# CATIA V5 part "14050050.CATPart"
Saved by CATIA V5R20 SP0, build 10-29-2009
Part number: 14050050
Definition: NONE
Nomenclature: 14050050
Source: Unknown
Description: 14050050
Bounding box of the stored display mesh (mm): x -25 to 100, y -39 to 29.1, z -29.1 to 29.1
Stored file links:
  C:\Users\Utente\Desktop\IO LAVORO\3D X SITO CF\X SITO\PLASTICA\RF2\14050050.CATPart

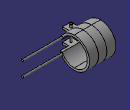
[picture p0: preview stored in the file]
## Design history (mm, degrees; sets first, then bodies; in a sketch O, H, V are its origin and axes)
Body1 "14050050" (main body)
  Solid1: solid without history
